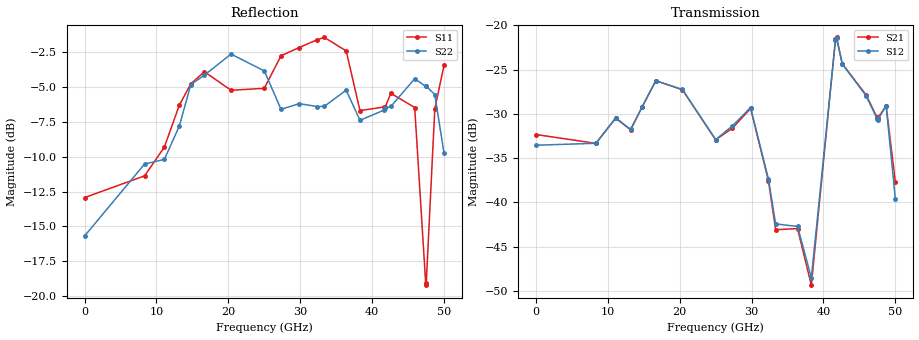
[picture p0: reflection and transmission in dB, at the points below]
!Keysight Technologies,N5245B,MY58422270,A.16.20.02
!Date: Thursday, March 05, 2026 01:45:19
!Correction: S11(C  2-Port  )
!S21(C  2-Port  )
!S12(C  2-Port  )
!S22(C  2-Port  )
!S2P File: Measurements: S11, S21, S12, S22:
# Hz S  dB  R 50
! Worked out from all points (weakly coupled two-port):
!   3201 points, 10 MHz to 50 GHz, reference 50 ohm
!   highest |S21| = -21.36 dB at 41.83 GHz (marker M1); lowest = -49.3 dB at 38.31 GHz (marker M2)
!   lowest |S11| = -19.2 dB at 47.52 GHz (marker M3), VSWR 1.25, Z = 45 + j9.17 ohm
!   |S11| at or under -10 dB: start of sweep to 10.02 GHz; 11.36 GHz to 11.93 GHz (571 MHz wide, 4.9 % of centre); 46.69 GHz to 48.24 GHz (1.548 GHz wide, 3.26 % of centre)
!   |S22| runs from -20.1 to -2.5 dB; largest |S21 - S12| = 0.0086
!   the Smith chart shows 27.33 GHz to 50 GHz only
!   S11 on the Smith chart (normalised r, x): 27.33 GHz: 0.18, +0.38; 32.35 GHz: 0.43, +1.88; 36.39 GHz: 2.31, -3.30; 42.61 GHz: 0.93, -1.22; 47.45 GHz: 0.86, +0.15; 50 GHz: 0.62, -1.38
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1e7  -12.93 -2.5  -32.33 -2.7  -33.54 7.8  -15.69 42.5
8.352081e9  -11.37 174.9  -33.33 33.2  -33.32 33.5  -10.52 179.2
1.110153e10  -9.31 107.8  -30.49 -59.2  -30.44 -58.9  -10.19 81.9
1.317924e10  -6.30 63.1  -31.81 -109.6  -31.76 -109.8  -7.80 -24.4
1.478829e10  -4.75 11.9  -29.20 -143.7  -29.19 -143.5  -4.81 -92.3
1.667854e10  -3.89 -43.9  -26.25 159.9  -26.27 160.1  -4.13 -142.7
2.038092e10  -5.22 -121.2  -27.28 41.3  -27.23 41.3  -2.62 153.7
2.5005e10  -5.08 -178.9  -32.93 -64.6  -32.90 -64.8  -3.83 71.1
2.733266e10  -2.74 137.8  -31.62 -116.5  -31.36 -114.8  -6.59 30.2
2.98634e10  -2.15 93.6  -29.39 157.3  -29.28 157.2  -6.18 -29.0
3.234728e10  -1.59 54.1  -37.56 44.7  -37.36 42.0  -6.39 -106.9
3.334708e10  -1.42 36.1  -43.08 2.6  -42.43 3.1  -6.38 -129.5
3.639335e10  -2.39 -23.4  -42.96 113.8  -42.71 111.5  -5.21 169.1
3.831484e10  -6.68 -22.2  -49.34 61.8  -48.52 -21.4  -7.38 137.4
4.167354e10  -6.42 -53.1  -21.53 -53.8  -21.65 -54.2  -6.64 112.7
4.182976e10  -6.40 -53.1  -21.36 -68.8  -21.46 -69.3  -6.52 111.2
4.261085e10  -5.44 -61.1  -24.33 -119.7  -24.36 -120.7  -6.38 107.4
4.592269e10  -6.46 -116.6  -27.84 47.4  -27.95 47.7  -4.39 62.6
4.745363e10  -19.09 127.4  -30.40 -9.6  -30.54 -11.1  -4.94 43.7
4.751612e10  -19.22 113.0  -30.50 -10.2  -30.71 -12.3  -4.92 43.0
4.871901e10  -6.56 -22.1  -29.10 -87.5  -29.09 -86.0  -5.53 20.0
5e10  -3.43 -64.9  -37.68 -121.1  -39.62 -143.9  -9.73 6.6
